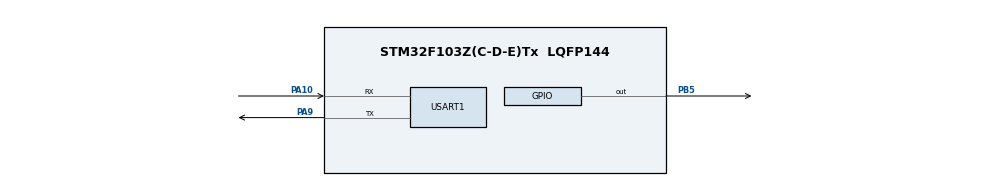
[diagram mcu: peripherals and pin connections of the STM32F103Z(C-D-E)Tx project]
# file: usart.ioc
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Mcu.Family=STM32F1
Mcu.Name=STM32F103Z(C-D-E)Tx
Mcu.Package=LQFP144
NVIC.PriorityGroup=NVIC_PRIORITYGROUP_4
NVIC.USART1_IRQn=true\:3\:0\:true\:false\:true\:true\:true\:true
OSC_IN.Mode=HSE-External-Oscillator
OSC_IN.Signal=RCC_OSC_IN
OSC_OUT.Mode=HSE-External-Oscillator
OSC_OUT.Signal=RCC_OSC_OUT
PA10.GPIO_PuPd=GPIO_NOPULL
PA10.Mode=Asynchronous
PA10.Signal=USART1_RX
PA13.Mode=Serial_Wire
PA13.Signal=SYS_JTMS-SWDIO
PA14.Mode=Serial_Wire
PA14.Signal=SYS_JTCK-SWCLK
PA9.Mode=Asynchronous
PA9.Signal=USART1_TX
PB5.GPIO_PuPd=GPIO_PULLUP
PB5.GPIO_Speed=GPIO_SPEED_FREQ_HIGH
PB5.Signal=GPIO_Output
PC14-OSC32_IN.Mode=LSE-External-Oscillator
PC14-OSC32_IN.Signal=RCC_OSC32_IN
PC15-OSC32_OUT.Mode=LSE-External-Oscillator
PC15-OSC32_OUT.Signal=RCC_OSC32_OUT
ProjectManager.HeapSize=0x200
ProjectManager.StackSize=0x400
ProjectManager.TargetToolchain=CMake
RCC.AHBFreq_Value=72000000
RCC.APB1CLKDivider=RCC_HCLK_DIV2
RCC.APB1Freq_Value=36000000
RCC.APB1TimFreq_Value=72000000
RCC.APB2Freq_Value=72000000
RCC.APB2TimFreq_Value=72000000
RCC.HCLKFreq_Value=72000000
RCC.PLLMUL=RCC_PLL_MUL9
RCC.PLLSourceVirtual=RCC_PLLSOURCE_HSE
RCC.SYSCLKFreq_VALUE=72000000
RCC.SYSCLKSource=RCC_SYSCLKSOURCE_PLLCLK
RCC.USBFreq_Value=72000000
USART1.VirtualMode=VM_ASYNC
board=custom

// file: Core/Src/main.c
/* USER CODE BEGIN Header */
/**
  ******************************************************************************
  * @file           : main.c
  * @brief          : Main program body
  ******************************************************************************
  * @attention
  *
  * Copyright (c) 2026 STMicroelectronics.
  * All rights reserved.
  *
  * This software is licensed under terms that can be found in the LICENSE file
  * in the root directory of this software component.
  * If no LICENSE file comes with this software, it is provided AS-IS.
  *
  ******************************************************************************
  */
/* USER CODE END Header */
#include "main.h"
#include "usart.h"
#include "gpio.h"

/* USER CODE BEGIN Includes */
#include <string.h>
#include <stdio.h>
/* USER CODE END Includes */

void SystemClock_Config(void);

  uint8_t rx_buffer[256];
  uint8_t rx_index = 0;

int main(void)
{

  /* MCU Configuration--------------------------------------------------------*/

  /* Reset of all peripherals, Initializes the Flash interface and the Systick. */
  HAL_Init();

  /* Configure the system clock */
  SystemClock_Config();

  /* Initialize all configured peripherals */
  MX_GPIO_Init();
  MX_USART1_UART_Init();
  /* USER CODE BEGIN 2 */

  // 启动测试信息
  // uint8_t welcome[] = "USART Ready!\r\n";
  // HAL_UART_Transmit(&huart1, welcome, sizeof(welcome)-1, 100);

  // // 启动中断接收
  // HAL_UART_Receive_IT(&huart1, &rx_buffer[0], 1);
   printf("=== STM32F103 USART Printf Test ===\r\n");
  /* USER CODE END 2 */
   int counter = 0;
  /* Infinite loop */
  /* USER CODE BEGIN WHILE */

  while (1)
  {
    // HAL_UART_Transmit(&huart1, tx_data, strlen((const char*)tx_data), 1000);
    // HAL_Delay(1000);

    // if (HAL_UART_Receive(&huart1, &rx_data, 1, 100) == HAL_OK)
    // {
    //   /* 发送提示信息 */
    //   HAL_UART_Transmit(&huart1, tx_msg, sizeof(tx_msg)-1, 100);
    printf("Counter: %d\r\n", counter++);
    HAL_Delay(1000);
    //   /* 回显接收到的数据 */
    //   HAL_UART_Transmit(&huart1, &rx_data, 1, 100);

    //   /* 发送换行符 */
    //   uint8_t newline[] = "\r\n";
    //   HAL_UART_Transmit(&huart1, newline, 2, 100);

  }

  /* USER CODE END 3 */
}

void SystemClock_Config(void)
{
  RCC_OscInitTypeDef RCC_OscInitStruct = {0};
  RCC_ClkInitTypeDef RCC_ClkInitStruct = {0};

  /** 使用内部HSI时钟，不使用PLL，最稳定配置
  */
  RCC_OscInitStruct.OscillatorType = RCC_OSCILLATORTYPE_HSI;
  RCC_OscInitStruct.HSIState = RCC_HSI_ON;
  RCC_OscInitStruct.HSICalibrationValue = RCC_HSICALIBRATION_DEFAULT;
  RCC_OscInitStruct.PLL.PLLState = RCC_PLL_NONE;  // 不使用PLL
  if (HAL_RCC_OscConfig(&RCC_OscInitStruct) != HAL_OK)
  {
    Error_Handler();
  }

  /** 系统时钟 = HSI = 8MHz
  */
  RCC_ClkInitStruct.ClockType = RCC_CLOCKTYPE_HCLK|RCC_CLOCKTYPE_SYSCLK
                              |RCC_CLOCKTYPE_PCLK1|RCC_CLOCKTYPE_PCLK2;
  RCC_ClkInitStruct.SYSCLKSource = RCC_SYSCLKSOURCE_HSI;  // 直接使用HSI
  RCC_ClkInitStruct.AHBCLKDivider = RCC_SYSCLK_DIV1;
  RCC_ClkInitStruct.APB1CLKDivider = RCC_HCLK_DIV1;
  RCC_ClkInitStruct.APB2CLKDivider = RCC_HCLK_DIV1;

  if (HAL_RCC_ClockConfig(&RCC_ClkInitStruct, FLASH_LATENCY_0) != HAL_OK)
  {
    Error_Handler();
  }
}

void Error_Handler(void)
{
  __disable_irq();
  while (1)
  {
  }
}
